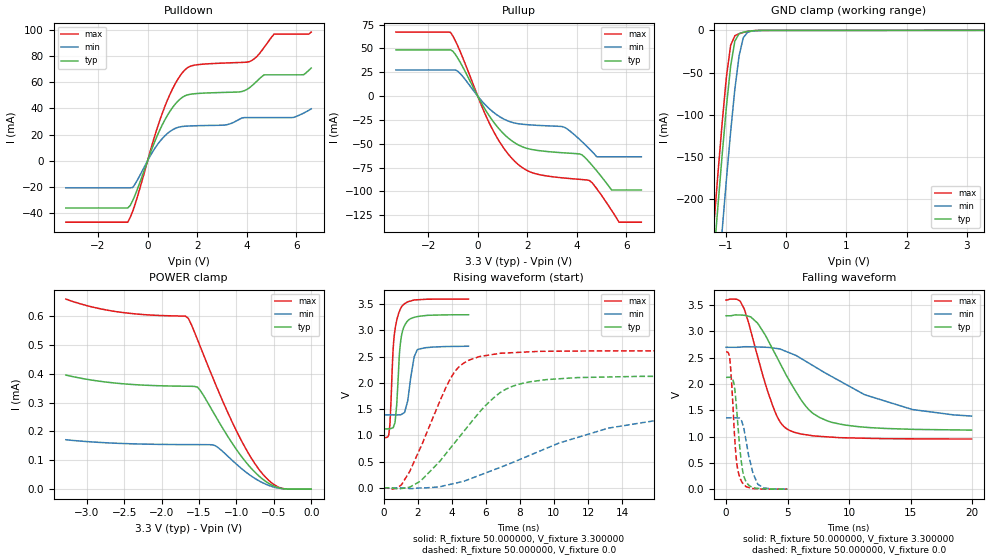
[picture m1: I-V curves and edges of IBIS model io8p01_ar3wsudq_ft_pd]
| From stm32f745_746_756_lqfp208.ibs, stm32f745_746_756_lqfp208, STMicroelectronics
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|   Model io8p01_ar3wsudq_ft_pd
[Model]  io8p01_ar3wsudq_ft_pd
Model_type I/O
Polarity   Non-Inverting
Enable   Active-Low
Vinl =   0.990000V
Vinh =   2.310000V
Vmeas =  1.650000V
Cref =   50.000000pF
Rref =   100.000000M
Vref =   0.0V
C_comp   3.843200pF   3.762100pF   3.937000pF
[Temperature Range]   25.000000   0.125000k   -40.000000
[Pullup Reference]   3.300000V   2.700000V   3.600000V
[Pulldown Reference]   0.0V   0.0V   0.0V
[POWER Clamp Reference]   3.300000V   2.700000V   3.600000V
[GND Clamp Reference]   0.0V   0.0V   0.0V
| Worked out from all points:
|   slope of the pulldown table from 0 to 0.495 V, typ, clamps not added: 20.9 ohm
|   slope of the pullup table from 0 to 0.495 V, typ, clamps not added: 22.6 ohm
|   GND clamp passes 1 mA (typ) near -0.62 V on its own axis
|   rising waveform, R_fixture 50.000000, V_fixture 3.300000: 20-80 % time 270ps typ, 352ps min, 283ps max; typ from 1.12 V to 3.3 V
|   rising waveform, R_fixture 50.000000, V_fixture 0.0: 20-80 % time 3.35ns typ, 6.78ns min, 2.11ns max; typ from 0 V to 2.13 V
|   falling waveform, R_fixture 50.000000, V_fixture 3.300000: 20-80 % time 3.21ns typ, 6.81ns min, 2.02ns max; typ from 3.3 V to 1.12 V
|   falling waveform, R_fixture 50.000000, V_fixture 0.0: 20-80 % time 504ps typ, 745ps min, 424ps max; typ from 2.13 V to 0 V
[Pulldown]
|Voltage   I(typ)   I(min)   I(max)
-3.3V     -36.18mA   -20.77mA   -47.07mA
-800mV    -36.18mA   -20.77mA   -47.07mA
-600mV    -30.5mA    -20.52mA   -38.69mA
700mV     31.4mA     19.11mA    41.71mA
1.2V      45.15mA    25.37mA    61.75mA
1.6V      50.35mA    26.5mA     71.06mA
3.1V      52.27mA    27.26mA    74.75mA
4.1V      55.7mA     33.01mA    75.8mA
4.7V      65.73mA    33.01mA    86.69mA
5.1V      65.73mA    33.01mA    96.89mA
6.3V      65.85mA    36.49mA    96.89mA
6.6V      70.9mA     39.7mA     98.44mA
[Pullup]
|Voltage   I(typ)   I(min)   I(max)
-3.3V     48.54mA    27.45mA    67.15mA
-1.1V     48.54mA    27.45mA    66.87mA
-700mV    35.13mA    23.48mA    46.33mA
500mV     -22.07mA   -14mA      -30.03mA
1.5V      -49.1mA    -28.3mA    -68.56mA
2.2V      -56.04mA   -30.32mA   -80.35mA
3.5V      -59.53mA   -32.72mA   -85.92mA
4.5V      -69.21mA   -55.27mA   -88.44mA
4.8V      -78.37mA   -63.6mA    -97.02mA
5.4V      -98.4mA    -63.6mA    -119.7mA
5.7V      -98.4mA    -63.6mA    -132.2mA
6.6V      -98.4mA    -63.6mA    -132.2mA
[GND_clamp]
|Voltage   I(typ)   I(min)   I(max)
-3.3V     -2.325A    -2.404A    -2.299A
-1.2V     -270.2mA   -361.4mA   -232.1mA
-1.13V    -207.3mA   -298.1mA   -169mA
-1.06V    -146.7mA   -236.2mA   -108.8mA
-990mV    -90.18mA   -176.4mA   -54.97mA
-920mV    -42.21mA   -120mA     -17.69mA
-850mV    -12.58mA   -69.47mA   -6.279mA
-780mV    -3.983mA   -30.01mA   -3.9mA
-710mV    -2.112mA   -8.623mA   -2.396mA
-640mV    -1.159mA   -2.292mA   -1.234mA
-570mV    -535.1uA   -830.5uA   -490.2uA
3.28V     81.28uA    57.87uA    93.98uA
[POWER_clamp]
|Voltage   I(typ)   I(min)   I(max)
-3.28V    395.3uA    171.3uA    658.7uA
-2.6V     367.1uA    159uA      614.9uA
-1.68V    356.7uA    154.4uA    599.4uA
-1.64V    356.5uA    154.4uA    590.8uA
-1.52V    353.6uA    154.3uA    518.3uA
-1.48V    341.1uA    154.2uA    492.3uA
-1.28V    253.6uA    150.4uA    364.2uA
-960mV    123.1uA    77.56uA    181.6uA
-720mV    50.52uA    32.03uA    76.18uA
-560mV    18.94uA    12.27uA    28.65uA
-440mV    5.104uA    3.69uA     7.327uA
0V        0A         0A         0A
[Ramp]
| variable   typ   min   max
dV/dt_r  1.27812/3.35922n   0.79776/6.76789n   1.56636/2.11275n
dV/dt_f  1.30194/3.21401n   0.74100/6.77912n   1.58738/2.02043n
R_load = 50.000000
[Rising Waveform]
R_fixture= 50.000000
V_fixture= 3.300000
V_fixture_min= 2.700000
V_fixture_max= 3.600000
|time   V(typ)   V(min)   V(max)
0s        1.123V     1.391V     953.9mV
360.4ps   1.126V     1.391V     1.185V
550.6ps   1.144V     1.391V     2.614V
660.7ps   1.236V     1.39V      3V
930.9ps   2.569V     1.392V     3.369V
1.031ns   2.863V     1.396V     3.438V
1.411ns   3.182V     1.655V     3.546V
1.782ns   3.248V     2.479V     3.579V
1.982ns   3.263V     2.635V     3.584V
4.985ns   3.299V     2.699V     3.598V
[Rising Waveform]
R_fixture= 50.000000
V_fixture= 0.0
V_fixture_min= 0.0
V_fixture_max= 0.0
|time   V(typ)   V(min)   V(max)
0s        357.3uV    204.3uV    681.7uV
1.041ns   -12.83mV   -1.324mV   56.47mV
2.162ns   126.4mV    -3.363mV   765.6mV
3.844ns   725.8mV    60.54mV    2.033V
4.364ns   935.4mV    98.84mV    2.285V
5.005ns   1.195V     160.8mV    2.432V
6.807ns   1.807V     384.6mV    2.563V
8.609ns   2.021V     623.3mV    2.593V
13.21ns   2.112V     1.138V     2.611V
19.94ns   2.128V     1.357V     2.611V
[Falling Waveform]
R_fixture= 50.000000
V_fixture= 3.300000
V_fixture_min= 2.700000
V_fixture_max= 3.600000
|time   V(typ)   V(min)   V(max)
0s        3.299V     2.699V     3.598V
920.9ps   3.313V     2.699V     3.608V
1.481ns   3.307V     2.709V     3.427V
2.563ns   3.158V     2.705V     2.526V
3.804ns   2.657V     2.686V     1.58V
5.045ns   2.105V     2.604V     1.132V
6.727ns   1.512V     2.397V     1.027V
8.609ns   1.27V      2.14V      989.3mV
15.14ns   1.139V     1.515V     957.7mV
19.94ns   1.123V     1.391V     953.9mV
[Falling Waveform]
R_fixture= 50.000000
V_fixture= 0.0
V_fixture_min= 0.0
V_fixture_max= 0.0
|time   V(typ)   V(min)   V(max)
0s        2.128V     1.357V     2.611V
300.3ps   2.129V     1.357V     2.489V
470.5ps   2.117V     1.357V     1.963V
620.6ps   2.029V     1.357V     1.315V
840.8ps   1.576V     1.359V     557.4mV
1.201ns   596.4mV    1.319V     176.8mV
1.622ns   146.7mV    928mV      49.83mV
2.182ns   33.62mV    307.5mV    12.06mV
2.583ns   15.14mV    93.93mV    6.521mV
4.985ns   357.3uV    204.3uV    681.7uV
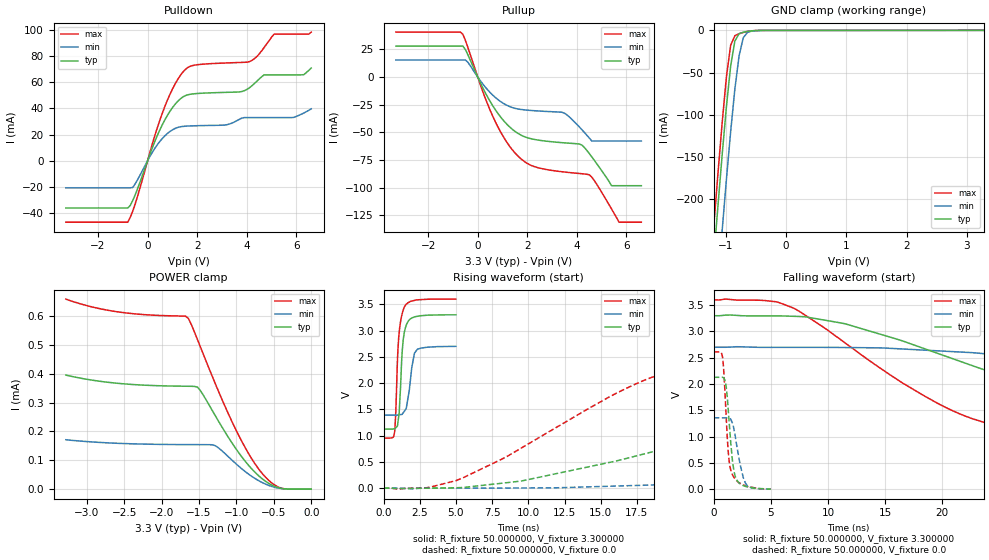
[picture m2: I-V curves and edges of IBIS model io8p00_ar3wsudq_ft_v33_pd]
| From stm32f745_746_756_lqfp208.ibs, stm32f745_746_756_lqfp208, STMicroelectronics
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|   Model io8p00_ar3wsudq_ft_v33_pd
[Model]  io8p00_ar3wsudq_ft_v33_pd
Model_type I/O
Polarity   Non-Inverting
Enable   Active-Low
Vinl =   0.990000V
Vinh =   2.310000V
Vmeas =  1.650000V
Cref =   50.000000pF
Rref =   100.000000M
Vref =   0.0V
C_comp   3.857500pF   3.762100pF   3.941700pF
[Temperature Range]   25.000000   0.125000k   -40.000000
[Pullup Reference]   3.300000V   2.700000V   3.600000V
[Pulldown Reference]   0.0V   0.0V   0.0V
[POWER Clamp Reference]   3.300000V   2.700000V   3.600000V
[GND Clamp Reference]   0.0V   0.0V   0.0V
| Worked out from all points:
|   slope of the pulldown table from 0 to 0.495 V, typ, clamps not added: 20.9 ohm
|   slope of the pullup table from 0 to 0.495 V, typ, clamps not added: 22.6 ohm
|   GND clamp passes 1 mA (typ) near -0.62 V on its own axis
|   rising waveform, R_fixture 50.000000, V_fixture 3.300000: 20-80 % time 276ps typ, 397ps min, 272ps max; typ from 1.12 V to 3.3 V
|   rising waveform, R_fixture 50.000000, V_fixture 0.0: 20-80 % time 19.7ns typ, 51.9ns min, 10.4ns max; typ from 0 V to 2.13 V
|   falling waveform, R_fixture 50.000000, V_fixture 3.300000: 20-80 % time 18.6ns typ, 38.4ns min, 11.3ns max; typ from 3.3 V to 1.12 V
|   falling waveform, R_fixture 50.000000, V_fixture 0.0: 20-80 % time 513ps typ, 708ps min, 436ps max; typ from 2.13 V to 0 V
[Pulldown]
|Voltage   I(typ)   I(min)   I(max)
-3.3V     -36.18mA   -20.77mA   -47.07mA
-800mV    -36.18mA   -20.77mA   -47.07mA
-600mV    -30.5mA    -20.52mA   -38.69mA
700mV     31.4mA     19.11mA    41.71mA
1.2V      45.15mA    25.37mA    61.75mA
1.6V      50.35mA    26.5mA     71.06mA
3.1V      52.27mA    27.26mA    74.75mA
4.1V      55.7mA     32.99mA    75.8mA
4.7V      65.71mA    32.99mA    86.63mA
5.1V      65.71mA    32.99mA    96.88mA
6.3V      65.85mA    36.49mA    96.88mA
6.6V      70.9mA     39.7mA     98.44mA
[Pullup]
|Voltage   I(typ)   I(min)   I(max)
-3.3V     28.03mA    15.43mA    40.67mA
-700mV    28.03mA    15.43mA    40.67mA
-400mV    20.31mA    13.47mA    26.93mA
600mV     -25.77mA   -16.23mA   -35.13mA
1.6V      -50.64mA   -28.81mA   -70.96mA
2.3V      -56.49mA   -30.48mA   -81.16mA
3.5V      -59.53mA   -32.72mA   -85.92mA
4.2V      -61.52mA   -47.6mA    -87.46mA
4.5V      -69.21mA   -55.14mA   -88.44mA
5.4V      -98.3mA    -57.9mA    -119.4mA
5.7V      -98.3mA    -57.9mA    -131.3mA
6.6V      -98.3mA    -57.9mA    -131.3mA
[GND_clamp]
|Voltage   I(typ)   I(min)   I(max)
-3.3V     -2.333A    -2.407A    -2.313A
-1.2V     -270.2mA   -361.4mA   -232.1mA
-1.13V    -207.3mA   -298.1mA   -169mA
-1.06V    -146.7mA   -236.2mA   -108.8mA
-990mV    -90.18mA   -176.4mA   -54.97mA
-920mV    -42.21mA   -120mA     -17.69mA
-850mV    -12.58mA   -69.47mA   -6.279mA
-780mV    -3.983mA   -30.01mA   -3.9mA
-710mV    -2.112mA   -8.623mA   -2.396mA
-640mV    -1.159mA   -2.292mA   -1.234mA
-570mV    -535.1uA   -830.5uA   -490.2uA
3.28V     81.28uA    57.87uA    93.98uA
[POWER_clamp]
|Voltage   I(typ)   I(min)   I(max)
-3.28V    395.3uA    171.3uA    658.7uA
-2.6V     367.1uA    159uA      614.9uA
-1.68V    356.7uA    154.4uA    599.4uA
-1.64V    356.5uA    154.4uA    590.8uA
-1.52V    353.6uA    154.3uA    518.3uA
-1.48V    341.1uA    154.2uA    492.3uA
-1.28V    253.6uA    150.4uA    364.2uA
-960mV    123.1uA    77.55uA    181.6uA
-720mV    50.52uA    32.03uA    76.18uA
-560mV    18.94uA    12.27uA    28.65uA
-440mV    5.104uA    3.69uA     7.327uA
0V        0A         0A         0A
[Ramp]
| variable   typ   min   max
dV/dt_r  1.27668/19.66164n   0.81522/51.92057n   1.56654/10.38570n
dV/dt_f  1.30572/18.58654n   0.78528/38.57212n   1.58743/11.31090n
R_load = 50.000000
[Rising Waveform]
R_fixture= 50.000000
V_fixture= 3.300000
V_fixture_min= 2.700000
V_fixture_max= 3.600000
|time   V(typ)   V(min)   V(max)
0s        1.123V     1.39V      953.1mV
760.8ps   1.131V     1.39V      1.076V
840.8ps   1.15V      1.39V      1.456V
1.041ns   1.364V     1.394V     2.869V
1.281ns   2.597V     1.408V     3.32V
1.441ns   2.982V     1.469V     3.454V
1.562ns   3.1V       1.52V      3.5V
2.132ns   3.258V     2.57V      3.573V
2.332ns   3.271V     2.644V     3.584V
4.985ns   3.299V     2.699V     3.599V
[Rising Waveform]
R_fixture= 50.000000
V_fixture= 0.0
V_fixture_min= 0.0
V_fixture_max= 0.0
|time   V(typ)   V(min)   V(max)
0s        122.9nV    336.7nV    642.2nV
3.003ns   -461.2uV   -682.5uV   8.405mV
5.506ns   12.51mV    -96.65uV   200.1mV
19.02ns   722.6mV    63.66mV    2.156V
30.53ns   1.491V     229.7mV    2.528V
40.04ns   1.895V     386mV      2.58V
55.06ns   2.057V     671.2mV    2.604V
87.09ns   2.115V     1.113V     2.611V
117.6ns   2.128V     1.3V       2.611V
249.2ns   2.128V     1.358V     2.611V
[Falling Waveform]
R_fixture= 50.000000
V_fixture= 3.300000
V_fixture_min= 2.700000
V_fixture_max= 3.600000
|time   V(typ)   V(min)   V(max)
0s        3.299V     2.699V     3.599V
7.007ns   3.288V     2.697V     3.441V
16.52ns   2.819V     2.666V     2.019V
22.52ns   2.357V     2.597V     1.348V
32.53ns   1.666V     2.393V     1.062V
38.54ns   1.41V      2.26V      1.026V
47.55ns   1.262V     2.05V      993.2mV
62.56ns   1.183V     1.725V     967.2mV
89.59ns   1.144V     1.511V     954.9mV
249.2ns   1.123V     1.39V      953.1mV
[Falling Waveform]
R_fixture= 50.000000
V_fixture= 0.0
V_fixture_min= 0.0
V_fixture_max= 0.0
|time   V(typ)   V(min)   V(max)
0s        2.128V     1.358V     2.611V
780.8ps   2.126V     1.357V     2.489V
860.9ps   2.118V     1.357V     2.293V
1.091ns   1.941V     1.357V     1.358V
1.261ns   1.522V     1.352V     721.8mV
1.411ns   1.091V     1.341V     437.8mV
1.622ns   573.9mV    1.262V     282mV
1.962ns   198.5mV    893mV      169.3mV
2.763ns   53.2mV     118.9mV    62.26mV
4.985ns   122.9nV    336.7nV    642.2nV
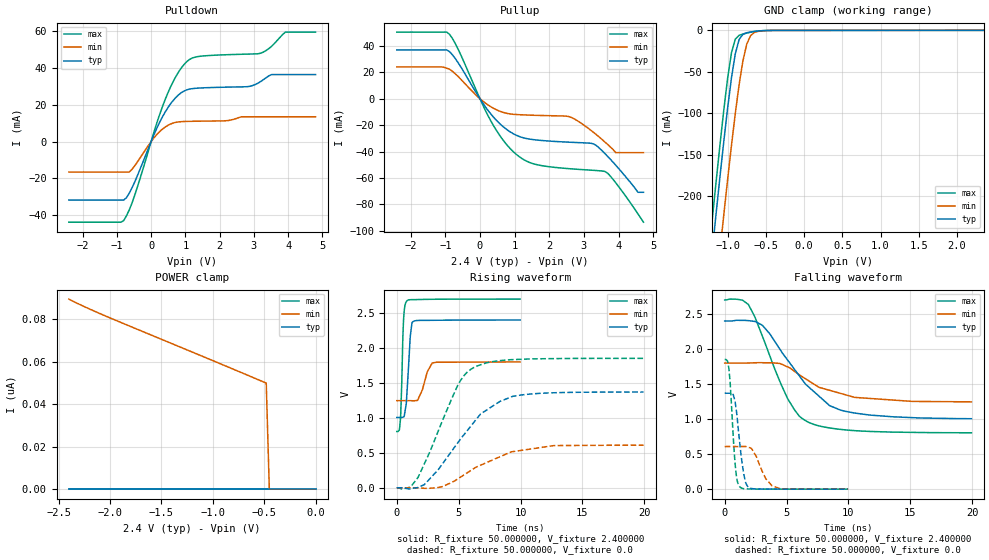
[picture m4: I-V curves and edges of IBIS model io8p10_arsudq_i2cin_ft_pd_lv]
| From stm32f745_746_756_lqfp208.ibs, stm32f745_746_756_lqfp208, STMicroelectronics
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|   Model io8p10_arsudq_i2cin_ft_pd_lv
[Model]  io8p10_arsudq_i2cin_ft_pd_lv
Model_type I/O
Polarity   Non-Inverting
Enable   Active-Low
Vinl =   0.720000V
Vinh =   1.680000V
Vmeas =  1.200000V
Cref =   40.000000pF
Rref =   100.000000M
Vref =   0.0V
C_comp   2.230300pF   2.174000pF   2.332300pF
[Temperature Range]   25.000000   0.125000k   -40.000000
[Pullup Reference]   2.400000V   1.800000V   2.700000V
[Pulldown Reference]   0.0V   0.0V   0.0V
[POWER Clamp Reference]   2.400000V   1.800000V   2.700000V
[GND Clamp Reference]   0.0V   0.0V   0.0V
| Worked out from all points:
|   slope of the pulldown table from 0 to 0.36 V, typ, clamps not added: 25 ohm
|   slope of the pullup table from 0 to 0.36 V, typ, clamps not added: 27.7 ohm
|   GND clamp passes 1 mA (typ) near -0.62 V on its own axis
|   rising waveform, R_fixture 50.000000, V_fixture 2.400000: 20-80 % time 278ps typ, 607ps min, 184ps max; typ from 1 V to 2.4 V
|   rising waveform, R_fixture 50.000000, V_fixture 0.0: 20-80 % time 3.71ns typ, 4.01ns min, 2.67ns max; typ from 0 V to 1.37 V
|   falling waveform, R_fixture 50.000000, V_fixture 2.400000: 20-80 % time 3.89ns typ, 3.98ns min, 2.72ns max; typ from 2.4 V to 1 V
|   falling waveform, R_fixture 50.000000, V_fixture 0.0: 20-80 % time 529ps typ, 975ps min, 384ps max; typ from 1.37 V to 0 V
[Pulldown]
|Voltage   I(typ)   I(min)   I(max)
-2.4V     -31.73mA   -16.51mA   -43.74mA
-800mV    -31.73mA   -16.51mA   -42.87mA
-480mV    -21.98mA   -13.17mA   -29.2mA
80mV      3.63mA     1.966mA    5.014mA
480mV     18.15mA    8.738mA    26.02mA
800mV     25.38mA    10.72mA    37.77mA
1.12V     28.53mA    11.02mA    44.6mA
2.8V      29.84mA    13.49mA    47.53mA
3.2V      32.65mA    13.49mA    48.04mA
3.52V     36.42mA    13.49mA    51.83mA
3.92V     36.42mA    13.49mA    59.49mA
4.8V      36.42mA    13.49mA    59.49mA
[Pullup]
|Voltage   I(typ)   I(min)   I(max)
-2.4V     36.91mA    24.03mA    50.37mA
-960mV    36.91mA    23.05mA    50.37mA
-640mV    27.65mA    17.03mA    37.99mA
320mV     -11.75mA   -6.207mA   -17.08mA
960mV     -26.47mA   -11.82mA   -40.02mA
1.52V     -30.88mA   -12.51mA   -49.05mA
2.56V     -32.88mA   -13.48mA   -52.9mA
3.28V     -34.19mA   -25.52mA   -54.18mA
3.6V      -41.31mA   -32.62mA   -54.97mA
3.92V     -50.32mA   -40.8mA    -63.63mA
4.56V     -70.8mA    -40.8mA    -87.08mA
4.72V     -70.8mA    -40.8mA    -93.4mA
[GND_clamp]
|Voltage   I(typ)   I(min)   I(max)
-2.4V     -1.424A    -1.508A    -1.393A
-1.25V    -311.2mA   -401.9mA   -273.3mA
-1.2V     -265.4mA   -356.1mA   -227.2mA
-1.15V    -220.4mA   -310.8mA   -181.9mA
-1.1V     -176.3mA   -266.2mA   -137.9mA
-1.05V    -133.8mA   -222.5mA   -95.87mA
-950mV    -57.3mA    -138.9mA   -26.99mA
-900mV    -28.28mA   -100.4mA   -10.6mA
-850mV    -11.02mA   -65.54mA   -5.972mA
-750mV    -2.846mA   -16.51mA   -3.192mA
-600mV    -761.3uA   -1.173mA   -751.9uA
2.35V     58.09uA    37.92uA    67.25uA
[POWER_clamp]
|Voltage   I(typ)   I(min)   I(max)
-2.4V     0A         89.62nA    0A
-2.04V    0A         81.57nA    0A
-480mV    0A         50.01nA    0A
-450mV    0A         0A         0A
0V        0A         0A         0A
[Ramp]
| variable   typ   min   max
dV/dt_r  0.82140/3.70323n   0.36557/4.01414n   1.11078/2.67231n
dV/dt_f  0.83346/3.89446n   0.33294/4.04052n   1.13600/2.72263n
R_load = 50.000000
[Rising Waveform]
R_fixture= 50.000000
V_fixture= 2.400000
V_fixture_min= 1.800000
V_fixture_max= 2.700000
|time   V(typ)   V(min)   V(max)
0s        1.005V     1.245V     804.2mV
200.2ps   1.005V     1.245V     825.1mV
300.3ps   1.005V     1.245V     988.7mV
560.6ps   1.014V     1.246V     2.44V
820.8ps   1.353V     1.246V     2.673V
1.101ns   2.18V      1.245V     2.689V
1.341ns   2.38V      1.244V     2.69V
1.682ns   2.392V     1.252V     2.691V
2.883ns   2.395V     1.786V     2.695V
9.97ns    2.399V     1.799V     2.698V
[Rising Waveform]
R_fixture= 50.000000
V_fixture= 0.0
V_fixture_min= 0.0
V_fixture_max= 0.0
|time   V(typ)   V(min)   V(max)
0s        169.1uV    66.56uV    559.6uV
1.121ns   -14.43mV   129.7uV    14.51mV
1.722ns   5.603mV    -1.064mV   149.4mV
3.323ns   253.4mV    4.117mV    799mV
4.925ns   642.3mV    126.4mV    1.464V
6.246ns   939mV      277mV      1.721V
6.807ns   1.059V     325.4mV    1.761V
9.369ns   1.308V     516.9mV    1.833V
12.73ns   1.359V     603.3mV    1.847V
19.94ns   1.369V     608.4mV    1.851V
[Falling Waveform]
R_fixture= 50.000000
V_fixture= 2.400000
V_fixture_min= 1.800000
V_fixture_max= 2.700000
|time   V(typ)   V(min)   V(max)
0s        2.399V     1.799V     2.698V
1.441ns   2.408V     1.799V     2.695V
1.922ns   2.404V     1.8V       2.631V
3.043ns   2.338V     1.804V     2.183V
5.085ns   1.841V     1.744V     1.292V
6.006ns   1.623V     1.636V     1.047V
6.727ns   1.468V     1.553V     958.2mV
8.488ns   1.191V     1.41V      873.1mV
9.77ns    1.11V      1.346V     845.1mV
19.94ns   1.005V     1.245V     804.2mV
[Falling Waveform]
R_fixture= 50.000000
V_fixture= 0.0
V_fixture_min= 0.0
V_fixture_max= 0.0
|time   V(typ)   V(min)   V(max)
0s        1.369V     608.4mV    1.851V
340.3ps   1.369V     608.4mV    1.717V
440.4ps   1.369V     608.4mV    1.52V
700.7ps   1.342V     608.3mV    718.3mV
940.9ps   1.121V     608mV      197.1mV
1.221ns   650.7mV    607.9mV    34.2mV
1.542ns   212.1mV    608.9mV    6.783mV
2.022ns   17.91mV    591.1mV    2.687mV
3.844ns   1.284mV    46.71mV    1.333mV
9.97ns    169.1uV    66.56uV    559.6uV
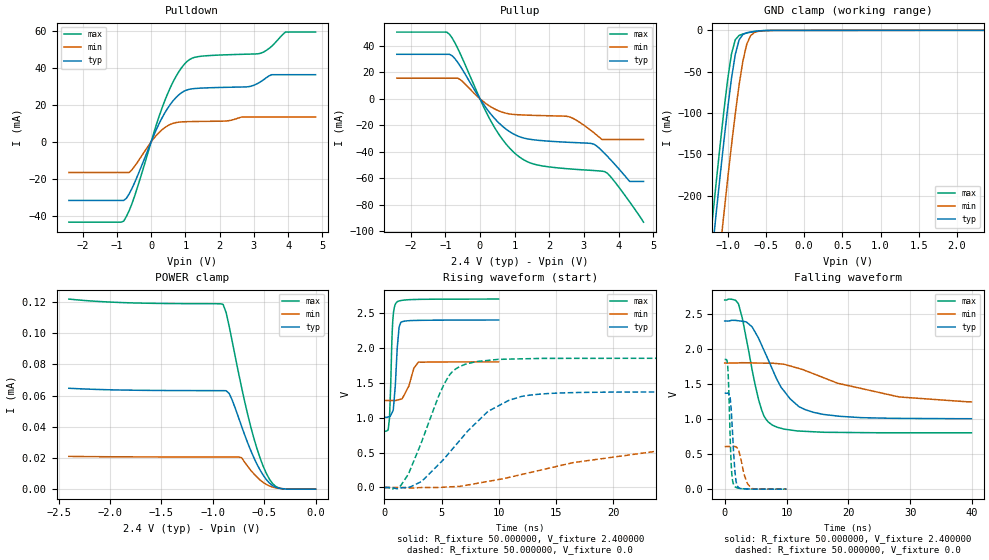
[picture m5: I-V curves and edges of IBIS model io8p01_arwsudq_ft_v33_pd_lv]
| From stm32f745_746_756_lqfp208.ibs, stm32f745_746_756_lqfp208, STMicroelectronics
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|   Model io8p01_arwsudq_ft_v33_pd_lv
[Model]  io8p01_arwsudq_ft_v33_pd_lv
Model_type I/O
Polarity   Non-Inverting
Enable   Active-Low
Vinl =   0.720000V
Vinh =   1.680000V
Vmeas =  1.200000V
Cref =   50.000000pF
Rref =   100.000000M
Vref =   0.0V
C_comp   2.828400pF   2.771400pF   2.910300pF
[Temperature Range]   25.000000   0.125000k   -40.000000
[Pullup Reference]   2.400000V   1.800000V   2.700000V
[Pulldown Reference]   0.0V   0.0V   0.0V
[POWER Clamp Reference]   2.400000V   1.800000V   2.700000V
[GND Clamp Reference]   0.0V   0.0V   0.0V
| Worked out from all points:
|   slope of the pulldown table from 0 to 0.36 V, typ, clamps not added: 25 ohm
|   slope of the pullup table from 0 to 0.36 V, typ, clamps not added: 27.7 ohm
|   GND clamp passes 1 mA (typ) near -0.62 V on its own axis
|   rising waveform, R_fixture 50.000000, V_fixture 2.400000: 20-80 % time 323ps typ, 711ps min, 222ps max; typ from 1 V to 2.4 V
|   rising waveform, R_fixture 50.000000, V_fixture 0.0: 20-80 % time 4.72ns typ, 12.1ns min, 2.67ns max; typ from 0 V to 1.37 V
|   falling waveform, R_fixture 50.000000, V_fixture 2.400000: 20-80 % time 5ns typ, 13ns min, 2.68ns max; typ from 2.4 V to 1 V
|   falling waveform, R_fixture 50.000000, V_fixture 0.0: 20-80 % time 552ps typ, 1.05ns min, 407ps max; typ from 1.37 V to 0 V
[Pulldown]
|Voltage   I(typ)   I(min)   I(max)
-2.4V     -31.66mA   -16.51mA   -43.43mA
-800mV    -31.66mA   -16.51mA   -42.86mA
-480mV    -21.98mA   -13.17mA   -29.2mA
80mV      3.63mA     1.966mA    5.014mA
480mV     18.15mA    8.738mA    26.02mA
800mV     25.38mA    10.72mA    37.77mA
1.12V     28.53mA    11.02mA    44.6mA
2.8V      29.84mA    13.48mA    47.53mA
3.2V      32.65mA    13.48mA    48.04mA
3.52V     36.42mA    13.48mA    51.83mA
3.92V     36.42mA    13.48mA    59.48mA
4.8V      36.42mA    13.48mA    59.48mA
[Pullup]
|Voltage   I(typ)   I(min)   I(max)
-2.4V     33.56mA    15.57mA    50.34mA
-960mV    33.56mA    15.57mA    50.34mA
-800mV    32.44mA    15.57mA    45.78mA
-560mV    24.28mA    14.31mA    33.53mA
320mV     -11.75mA   -6.207mA   -17.08mA
960mV     -26.47mA   -11.82mA   -40.02mA
1.52V     -30.88mA   -12.51mA   -49.05mA
2.56V     -32.88mA   -13.49mA   -52.9mA
3.28V     -34.2mA    -25.51mA   -54.18mA
3.6V      -41.34mA   -30.76mA   -55mA
4.32V     -62.43mA   -30.76mA   -77.88mA
4.72V     -62.43mA   -30.76mA   -93.2mA
[GND_clamp]
|Voltage   I(typ)   I(min)   I(max)
-2.4V     -1.428A    -1.51A     -1.4A
-1.2V     -266.4mA   -356.3mA   -229.4mA
-1.15V    -221.3mA   -311mA     -184.1mA
-1.1V     -177.3mA   -266.4mA   -140mA
-1.05V    -134.8mA   -222.7mA   -97.98mA
-950mV    -58.22mA   -139.2mA   -28.55mA
-900mV    -29.04mA   -100.6mA   -11.28mA
-850mV    -11.42mA   -65.77mA   -6.081mA
-750mV    -2.864mA   -16.63mA   -3.193mA
-700mV    -1.925mA   -6.327mA   -2.195mA
-600mV    -761.3uA   -1.176mA   -751.9uA
2.35V     58.09uA    37.92uA    67.25uA
[POWER_clamp]
|Voltage   I(typ)   I(min)   I(max)
-2.4V     64.71uA    21.03uA    121.9uA
-1.86V    63.55uA    20.74uA    119.6uA
-900mV    63.18uA    20.63uA    118.5uA
-870mV    63.14uA    20.63uA    113.2uA
-840mV    61.36uA    20.62uA    104.3uA
-720mV    40.37uA    20.18uA    65.28uA
-630mV    24.69uA    12.08uA    39.85uA
-540mV    12.26uA    5.907uA    20uA
-480mV    6.236uA    3.061uA    10.23uA
-420mV    2.4uA      1.365uA    3.726uA
-360mV    667.9nA    564nA      839.6nA
0V        0A         0A         0A
[Ramp]
| variable   typ   min   max
dV/dt_r  0.82164/4.71231n   0.38152/12.87060n   1.11030/2.66844n
dV/dt_f  0.83700/5.00385n   0.32262/13.04754n   1.13709/2.68087n
R_load = 50.000000
[Rising Waveform]
R_fixture= 50.000000
V_fixture= 2.400000
V_fixture_min= 1.800000
V_fixture_max= 2.700000
|time   V(typ)   V(min)   V(max)
0s        1.005V     1.245V     804.5mV
320.3ps   1.01V      1.245V     823.2mV
440.4ps   1.015V     1.245V     991.1mV
720.7ps   1.09V      1.245V     2.368V
940.9ps   1.443V     1.245V     2.62V
1.041ns   1.754V     1.248V     2.648V
1.281ns   2.298V     1.258V     2.671V
1.461ns   2.368V     1.266V     2.678V
2.963ns   2.394V     1.796V     2.694V
9.97ns    2.399V     1.799V     2.699V
[Rising Waveform]
R_fixture= 50.000000
V_fixture= 0.0
V_fixture_min= 0.0
V_fixture_max= 0.0
|time   V(typ)   V(min)   V(max)
0s        86.79uV    35.83uV    200.4uV
1.361ns   -9.078mV   -362.6uV   17.04mV
2.082ns   3.157mV    -5.824mV   188.2mV
5.205ns   409.6mV    4.315mV    1.478V
6.006ns   563.9mV    11.06mV    1.669V
7.127ns   779.9mV    31.27mV    1.768V
9.049ns   1.09V      87.08mV    1.82V
12.73ns   1.324V     214.5mV    1.845V
25.23ns   1.369V     551.5mV    1.85V
39.88ns   1.369V     608.5mV    1.85V
[Falling Waveform]
R_fixture= 50.000000
V_fixture= 2.400000
V_fixture_min= 1.800000
V_fixture_max= 2.700000
|time   V(typ)   V(min)   V(max)
0s        2.399V     1.799V     2.699V
2.242ns   2.402V     1.801V     2.639V
4.404ns   2.318V     1.802V     1.718V
5.526ns   2.143V     1.799V     1.262V
6.406ns   1.97V      1.798V     1.036V
7.768ns   1.698V     1.797V     912mV
10.57ns   1.289V     1.758V     844.7mV
14.49ns   1.093V     1.641V     818.4mV
28.19ns   1.01V      1.316V     804.7mV
39.88ns   1.005V     1.245V     804.5mV
[Falling Waveform]
R_fixture= 50.000000
V_fixture= 0.0
V_fixture_min= 0.0
V_fixture_max= 0.0
|time   V(typ)   V(min)   V(max)
0s        1.369V     608.5mV    1.85V
460.5ps   1.37V      608.3mV    1.79V
660.7ps   1.366V     608.2mV    1.412V
1.041ns   1.152V     608mV      367.1mV
1.481ns   468.4mV    609.1mV    57.68mV
1.822ns   119.8mV    605.7mV    25.95mV
2.282ns   19.63mV    550mV      13.19mV
3.143ns   4.144mV    207.1mV    5.114mV
4.364ns   1.776mV    9.239mV    1.656mV
9.97ns    86.79uV    35.83uV    200.4uV
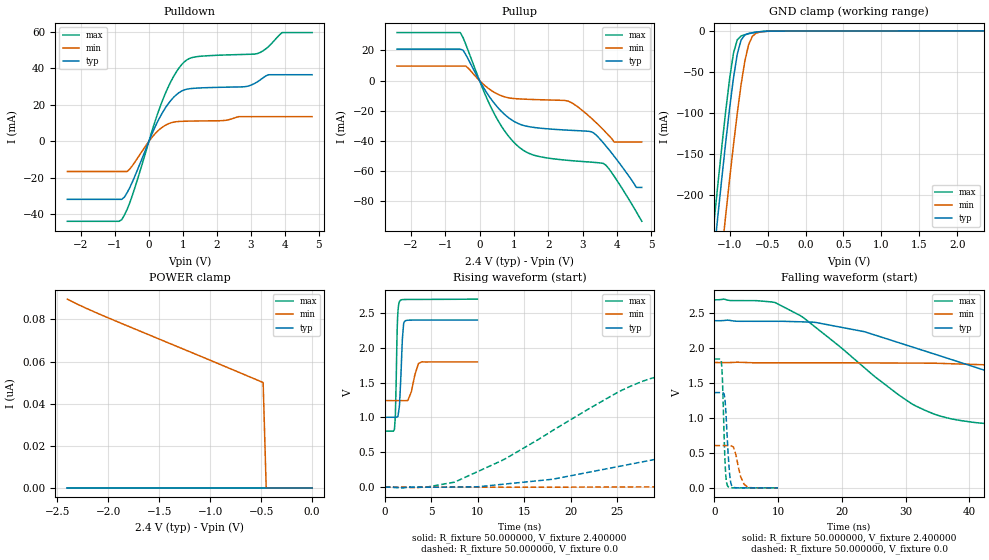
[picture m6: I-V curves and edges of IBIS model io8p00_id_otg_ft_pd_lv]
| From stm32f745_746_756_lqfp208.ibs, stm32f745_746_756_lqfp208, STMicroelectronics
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|   Model io8p00_id_otg_ft_pd_lv
[Model]  io8p00_id_otg_ft_pd_lv
Model_type I/O
Polarity   Non-Inverting
Enable   Active-Low
Vinl =   0.720000V
Vinh =   1.680000V
Vmeas =  1.200000V
Cref =   50.000000pF
Rref =   100.000000M
Vref =   0.0V
C_comp   2.229800pF   2.169700pF   2.325100pF
[Temperature Range]   25.000000   0.125000k   -40.000000
[Pullup Reference]   2.400000V   1.800000V   2.700000V
[Pulldown Reference]   0.0V   0.0V   0.0V
[POWER Clamp Reference]   2.400000V   1.800000V   2.700000V
[GND Clamp Reference]   0.0V   0.0V   0.0V
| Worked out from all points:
|   slope of the pulldown table from 0 to 0.36 V, typ, clamps not added: 25 ohm
|   slope of the pullup table from 0 to 0.36 V, typ, clamps not added: 27.7 ohm
|   GND clamp passes 1 mA (typ) near -0.62 V on its own axis
|   rising waveform, R_fixture 50.000000, V_fixture 2.400000: 20-80 % time 270ps typ, 604ps min, 182ps max; typ from 1 V to 2.4 V
|   rising waveform, R_fixture 50.000000, V_fixture 0.0: 20-80 % time 32.9ns typ, 82.2ns min, 14.6ns max; typ from 0 V to 1.37 V
|   falling waveform, R_fixture 50.000000, V_fixture 2.400000: 20-80 % time 29.6ns typ, 74.5ns min, 15.8ns max; typ from 2.4 V to 1 V
|   falling waveform, R_fixture 50.000000, V_fixture 0.0: 20-80 % time 522ps typ, 974ps min, 382ps max; typ from 1.37 V to 0 V
[Pulldown]
|Voltage   I(typ)   I(min)   I(max)
-2.4V     -31.73mA   -16.51mA   -43.74mA
-800mV    -31.73mA   -16.51mA   -42.87mA
-480mV    -21.97mA   -13.17mA   -29.2mA
80mV      3.629mA    1.966mA    5.013mA
480mV     18.15mA    8.736mA    26.01mA
800mV     25.37mA    10.71mA    37.77mA
1.12V     28.53mA    11.02mA    44.6mA
2.8V      29.83mA    13.48mA    47.51mA
3.2V      32.64mA    13.48mA    48.03mA
3.52V     36.41mA    13.48mA    51.82mA
3.92V     36.41mA    13.48mA    59.47mA
4.8V      36.41mA    13.48mA    59.47mA
[Pullup]
|Voltage   I(typ)   I(min)   I(max)
-2.4V     20.88mA    9.659mA    31.9mA
-560mV    20.88mA    9.659mA    31.9mA
-400mV    17.28mA    9.659mA    24.06mA
320mV     -11.75mA   -6.206mA   -17.08mA
960mV     -26.47mA   -11.82mA   -40.02mA
1.52V     -30.88mA   -12.51mA   -49.05mA
2.56V     -32.88mA   -13.48mA   -52.9mA
3.28V     -34.19mA   -25.52mA   -54.18mA
3.6V      -41.31mA   -32.62mA   -54.98mA
3.92V     -50.32mA   -40.8mA    -63.62mA
4.56V     -70.9mA    -40.8mA    -87.08mA
4.72V     -70.9mA    -40.8mA    -93.4mA
[GND_clamp]
|Voltage   I(typ)   I(min)   I(max)
-2.4V     -1.424A    -1.508A    -1.393A
-1.25V    -311.2mA   -401.9mA   -273.3mA
-1.2V     -265.4mA   -356.1mA   -227.2mA
-1.15V    -220.4mA   -310.8mA   -181.9mA
-1.1V     -176.3mA   -266.2mA   -137.9mA
-1.05V    -133.8mA   -222.5mA   -95.89mA
-950mV    -57.33mA   -138.9mA   -27.03mA
-900mV    -28.31mA   -100.4mA   -10.67mA
-850mV    -11.07mA   -65.56mA   -6.047mA
-750mV    -2.904mA   -16.55mA   -3.26mA
-600mV    -808.2uA   -1.212mA   -806.8uA
2.35V     242.6uA    152uA      283.9uA
[POWER_clamp]
|Voltage   I(typ)   I(min)   I(max)
-2.4V     0A         89.62nA    0A
-2.04V    0A         81.58nA    0A
-480mV    0A         50.01nA    0A
-450mV    0A         0A         0A
0V        0A         0A         0A
[Ramp]
| variable   typ   min   max
dV/dt_r  0.81942/32.88593n   0.36131/85.13700n   1.10850/14.58604n
dV/dt_f  0.83658/29.57145n   0.32832/79.61571n   1.13579/15.78053n
R_load = 50.000000
[Rising Waveform]
R_fixture= 50.000000
V_fixture= 2.400000
V_fixture_min= 1.800000
V_fixture_max= 2.700000
|time   V(typ)   V(min)   V(max)
0s        1.002V     1.241V     802.8mV
1.041ns   1.003V     1.242V     829.6mV
1.141ns   1.002V     1.242V     1.04V
1.381ns   1.011V     1.242V     2.438V
1.642ns   1.333V     1.242V     2.673V
1.902ns   2.137V     1.242V     2.689V
2.162ns   2.382V     1.24V      2.69V
2.843ns   2.395V     1.362V     2.691V
3.644ns   2.396V     1.773V     2.692V
9.97ns    2.396V     1.796V     2.696V
[Rising Waveform]
R_fixture= 50.000000
V_fixture= 0.0
V_fixture_min= 0.0
V_fixture_max= 0.0
|time   V(typ)   V(min)   V(max)
0s        4.159nV    252.6nV    1.587nV
7.508ns   2.136mV    -50.35uV   72.52mV
18.02ns   113.2mV    450.3uV    807.5mV
27.03ns   345.1mV    4.157mV    1.48V
32.03ns   478mV      10.29mV    1.661V
37.54ns   640.1mV    25.87mV    1.745V
58.06ns   1.111V     86.07mV    1.826V
76.58ns   1.302V     176.4mV    1.843V
148.1ns   1.364V     487.9mV    1.847V
249.2ns   1.366V     606.6mV    1.847V
[Falling Waveform]
R_fixture= 50.000000
V_fixture= 2.400000
V_fixture_min= 1.800000
V_fixture_max= 2.700000
|time   V(typ)   V(min)   V(max)
0s        2.396V     1.796V     2.696V
9.51ns    2.388V     1.792V     2.657V
16.02ns   2.369V     1.792V     2.291V
31.03ns   2.02V      1.788V     1.202V
36.54ns   1.859V     1.781V     1.003V
45.55ns   1.593V     1.755V     897.2mV
59.56ns   1.242V     1.706V     846.6mV
85.59ns   1.074V     1.56V      816.2mV
124.1ns   1.024V     1.378V     804.8mV
249.2ns   1.002V     1.241V     802.8mV
[Falling Waveform]
R_fixture= 50.000000
V_fixture= 0.0
V_fixture_min= 0.0
V_fixture_max= 0.0
|time   V(typ)   V(min)   V(max)
0s        1.366V     606.6mV    1.847V
1.061ns   1.365V     606.5mV    1.815V
1.241ns   1.366V     606.5mV    1.566V
1.682ns   1.229V     606.3mV    320.7mV
1.842ns   999.4mV    606mV      110.4mV
2.042ns   652mV      605.8mV    31.67mV
2.482ns   115.9mV    608.2mV    2.943mV
2.843ns   16.55mV    591.6mV    655.5uV
4.645ns   56.61uV    52.07mV    22.82uV
9.97ns    4.159nV    252.6nV    1.587nV
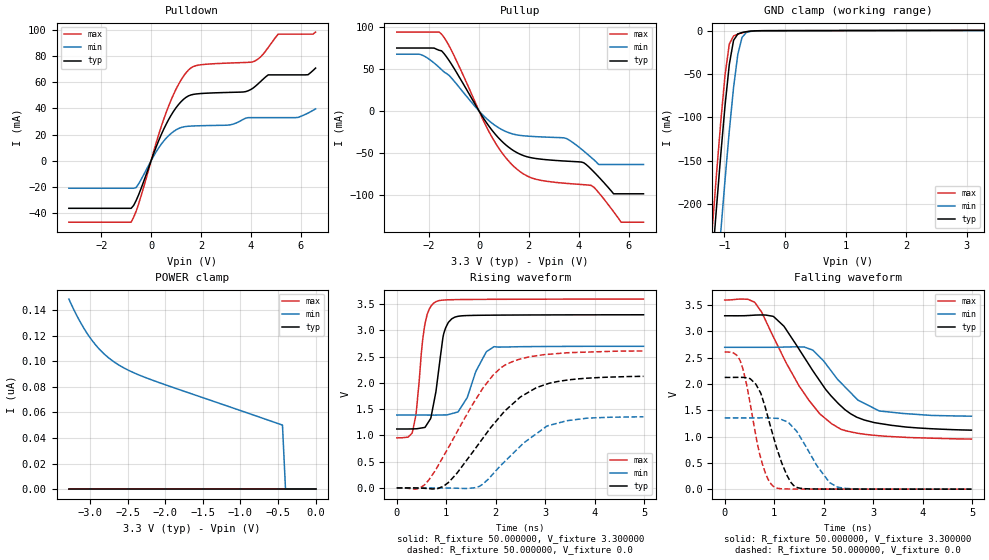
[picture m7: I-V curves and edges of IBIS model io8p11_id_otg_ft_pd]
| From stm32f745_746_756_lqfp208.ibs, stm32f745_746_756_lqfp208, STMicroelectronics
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|   Model io8p11_id_otg_ft_pd
[Model]  io8p11_id_otg_ft_pd
Model_type I/O
Polarity   Non-Inverting
Enable   Active-Low
Vinl =   0.990000V
Vinh =   2.310000V
Vmeas =  1.650000V
Cref =   30.000000pF
Rref =   100.000000M
Vref =   0.0V
C_comp   2.283100pF   2.214400pF   2.357400pF
[Temperature Range]   25.000000   0.125000k   -40.000000
[Pullup Reference]   3.300000V   2.700000V   3.600000V
[Pulldown Reference]   0.0V   0.0V   0.0V
[POWER Clamp Reference]   3.300000V   2.700000V   3.600000V
[GND Clamp Reference]   0.0V   0.0V   0.0V
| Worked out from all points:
|   slope of the pulldown table from 0 to 0.495 V, typ, clamps not added: 20.9 ohm
|   slope of the pullup table from 0 to 0.495 V, typ, clamps not added: 22.6 ohm
|   GND clamp passes 1 mA (typ) near -0.62 V on its own axis
|   rising waveform, R_fixture 50.000000, V_fixture 3.300000: 20-80 % time 198ps typ, 345ps min, 162ps max; typ from 1.12 V to 3.29 V
|   rising waveform, R_fixture 50.000000, V_fixture 0.0: 20-80 % time 1.13ns typ, 948ps min, 1ns max; typ from 0 V to 2.12 V
|   falling waveform, R_fixture 50.000000, V_fixture 3.300000: 20-80 % time 1.01ns typ, 783ps min, 983ps max; typ from 3.29 V to 1.12 V
|   falling waveform, R_fixture 50.000000, V_fixture 0.0: 20-80 % time 414ps typ, 536ps min, 330ps max; typ from 2.12 V to 0 V
[Pulldown]
|Voltage   I(typ)   I(min)   I(max)
-3.3V     -36.46mA   -21.1mA    -47.09mA
-800mV    -36.46mA   -21.1mA    -47.09mA
-600mV    -30.5mA    -20.54mA   -38.68mA
700mV     31.39mA    19.11mA    41.7mA
1.2V      45.14mA    25.37mA    61.74mA
1.6V      50.34mA    26.49mA    71.04mA
3.1V      52.26mA    27.25mA    74.74mA
4.1V      55.69mA    32.98mA    75.78mA
4.7V      65.7mA     32.98mA    86.67mA
5.1V      65.7mA     32.98mA    96.88mA
6.3V      65.85mA    36.49mA    96.88mA
6.6V      70.9mA     39.7mA     98.46mA
[Pullup]
|Voltage   I(typ)   I(min)   I(max)
-3.3V     74.72mA    67.4mA     93.64mA
-2.3V     74.72mA    66.56mA    93.64mA
-1.5V     71.36mA    49mA       91.07mA
500mV     -22.06mA   -14mA      -30.03mA
1.6V      -50.64mA   -28.8mA    -70.96mA
3.5V      -59.53mA   -32.65mA   -85.92mA
4.2V      -61.43mA   -47.48mA   -87.46mA
4.5V      -69.07mA   -55.13mA   -88.38mA
4.8V      -78.22mA   -63.5mA    -96.83mA
5.4V      -98.3mA    -63.5mA    -119.6mA
5.7V      -98.3mA    -63.5mA    -132mA
6.6V      -98.3mA    -63.5mA    -132mA
[GND_clamp]
|Voltage   I(typ)   I(min)   I(max)
-3.3V     -2.315A    -2.395A    -2.287A
-1.2V     -265.5mA   -356.1mA   -227.2mA
-1.13V    -202.7mA   -292.9mA   -164.2mA
-1.06V    -142.2mA   -231.2mA   -104.1mA
-990mV    -86mA      -171.6mA   -50.76mA
-920mV    -38.84mA   -115.5mA   -15.35mA
-850mV    -11.15mA   -65.63mA   -6.09mA
-780mV    -3.853mA   -27.45mA   -3.961mA
-710mV    -2.153mA   -7.739mA   -2.46mA
-640mV    -1.209mA   -2.169mA   -1.292mA
-570mV    -580.3uA   -846.3uA   -542.8uA
3.28V     342.5uA    239.2uA    398.5uA
[POWER_clamp]
|Voltage   I(typ)   I(min)   I(max)
-3.28V    0A         148.5nA    0A
-3.2V     0A         138.6nA    0A
-3.12V    0A         129.7nA    0A
-3.04V    0A         122nA      0A
-2.96V    0A         115.3nA    0A
-2.8V     0A         105.1nA    0A
-2.6V     0A         96.44nA    0A
-2.4V     0A         90.52nA    0A
-2.16V    0A         84.97nA    0A
-440mV    0A         50.04nA    0A
-400mV    0A         0A         0A
0V        0A         0A         0A
[Ramp]
| variable   typ   min   max
dV/dt_r  1.25832/1.11811n   0.80328/0.93930n   1.55742/0.99875n
dV/dt_f  1.27566/0.99597n   0.77142/0.75892n   1.56814/0.97751n
R_load = 50.000000
[Rising Waveform]
R_fixture= 50.000000
V_fixture= 3.300000
V_fixture_min= 2.700000
V_fixture_max= 3.600000
|time   V(typ)   V(min)   V(max)
0s        1.121V     1.387V     952.6mV
320.3ps   1.124V     1.387V     1.076V
390.4ps   1.125V     1.387V     1.41V
560.6ps   1.15V      1.387V     3.073V
690.7ps   1.341V     1.386V     3.458V
780.8ps   1.782V     1.386V     3.539V
951ps     2.943V     1.389V     3.576V
1.181ns   3.253V     1.432V     3.583V
1.962ns   3.288V     2.686V     3.589V
4.985ns   3.295V     2.695V     3.594V
[Rising Waveform]
R_fixture= 50.000000
V_fixture= 0.0
V_fixture_min= 0.0
V_fixture_max= 0.0
|time   V(typ)   V(min)   V(max)
0s        345.9uV    197.2uV    652.6uV
470.5ps   -2.817mV   136.4uV    -57.24uV
650.7ps   -14.05mV   197.4uV    155.2mV
951ps     37.18mV    -1.039mV   615mV
1.662ns   845.7mV    26.8mV     1.782V
2.192ns   1.473V     512.4mV    2.34V
2.503ns   1.734V     799.3mV    2.456V
3.043ns   1.98V      1.181V     2.541V
3.854ns   2.089V     1.328V     2.585V
4.985ns   2.123V     1.354V     2.606V
[Falling Waveform]
R_fixture= 50.000000
V_fixture= 3.300000
V_fixture_min= 2.700000
V_fixture_max= 3.600000
|time   V(typ)   V(min)   V(max)
0s        3.295V     2.695V     3.594V
600.6ps   3.307V     2.695V     3.554V
750.8ps   3.31V      2.695V     3.357V
991ps     3.277V     2.696V     2.881V
1.201ns   3.09V      2.7V       2.478V
1.772ns   2.264V     2.645V     1.607V
2.342ns   1.586V     2.027V     1.141V
2.693ns   1.359V     1.692V     1.062V
3.123ns   1.25V      1.487V     1.015V
4.985ns   1.121V     1.387V     952.6mV
[Falling Waveform]
R_fixture= 50.000000
V_fixture= 0.0
V_fixture_min= 0.0
V_fixture_max= 0.0
|time   V(typ)   V(min)   V(max)
0s        2.123V     1.354V     2.606V
310.3ps   2.124V     1.354V     2.447V
450.5ps   2.113V     1.354V     1.954V
720.7ps   1.838V     1.355V     619.9mV
870.9ps   1.379V     1.355V     200.2mV
1.011ns   908.1mV    1.348V     37.39mV
1.391ns   71.32mV    1.164V     2.889mV
1.872ns   3.187mV    432.7mV    1.882mV
2.282ns   1.72mV     39.02mV    1.564mV
4.985ns   345.9uV    197.2uV    652.6uV
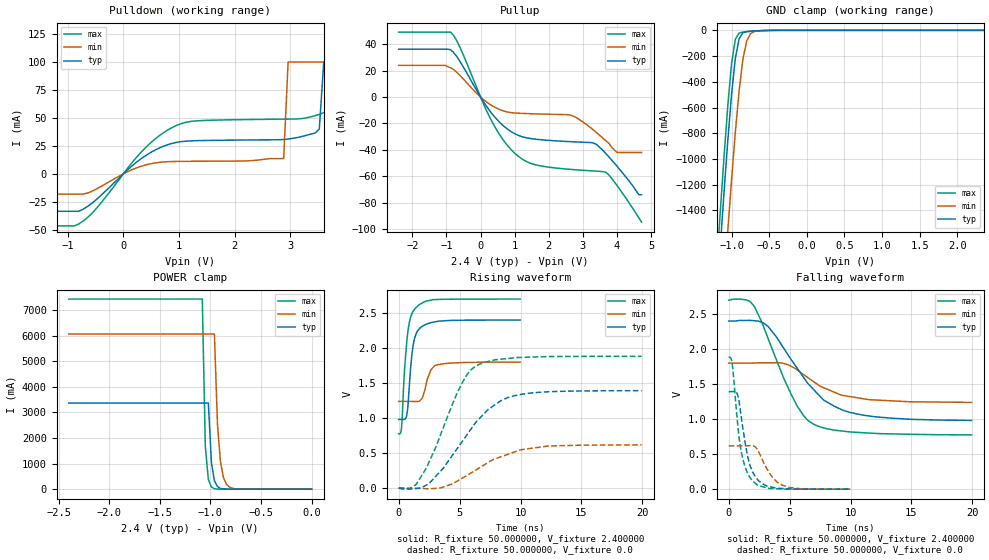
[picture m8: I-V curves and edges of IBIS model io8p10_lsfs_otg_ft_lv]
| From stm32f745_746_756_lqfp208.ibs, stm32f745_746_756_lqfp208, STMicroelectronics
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|   Model io8p10_lsfs_otg_ft_lv
[Model]  io8p10_lsfs_otg_ft_lv
Model_type I/O
Polarity   Non-Inverting
Enable   Active-Low
Vinl =   0.720000V
Vinh =   1.680000V
Vmeas =  1.200000V
Cref =   40.000000pF
Rref =   100.000000M
Vref =   0.0V
C_comp   7.971100pF   7.737700pF   8.264100pF
[Temperature Range]   25.000000   0.125000k   -40.000000
[Pullup Reference]   2.400000V   1.800000V   2.700000V
[Pulldown Reference]   0.0V   0.0V   0.0V
[POWER Clamp Reference]   2.400000V   1.800000V   2.700000V
[GND Clamp Reference]   0.0V   0.0V   0.0V
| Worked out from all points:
|   slope of the pulldown table from 0 to 0.36 V, typ, clamps not added: 24.1 ohm
|   slope of the pullup table from 0 to 0.36 V, typ, clamps not added: 26.8 ohm
|   GND clamp passes 1 mA (typ) near -0.52 V on its own axis
|   POWER clamp passes 1 mA (typ) near -0.81 V on its own axis
|   rising waveform, R_fixture 50.000000, V_fixture 2.400000: 20-80 % time 481ps typ, 595ps min, 491ps max; typ from 0.981 V to 2.4 V
|   rising waveform, R_fixture 50.000000, V_fixture 0.0: 20-80 % time 3.67ns typ, 4.11ns min, 2.72ns max; typ from 0 V to 1.39 V
|   falling waveform, R_fixture 50.000000, V_fixture 2.400000: 20-80 % time 3.73ns typ, 3.39ns min, 2.85ns max; typ from 2.4 V to 0.981 V
|   falling waveform, R_fixture 50.000000, V_fixture 0.0: 20-80 % time 916ps typ, 1.27ns min, 799ps max; typ from 1.39 V to 0 V
[Pulldown]
|Voltage   I(typ)   I(min)   I(max)
-2.4V     -33.44mA   -18.12mA   -46.52mA
-800mV    -33.44mA   -18.12mA   -44.78mA
1.04V     28.81mA    11.14mA    44.91mA
2.88V     30.71mA    13.65mA    48.89mA
2.96V     31.11mA    100mA      48.94mA
3.52V     40mA       100mA      53.15mA
3.6V      100mA      100mA      54.66mA
3.92V     100mA      100mA      60mA
4V        100mA      100mA      100mA
4.4V      100mA      100mA      100mA
4.48V     100mA      100mA      1A
4.8V      100mA      100mA      1A
[Pullup]
|Voltage   I(typ)   I(min)   I(max)
-2.4V     36.21mA    24mA       49.16mA
-880mV    35.81mA    22.16mA    49.16mA
-640mV    28.47mA    17.31mA    39.62mA
320mV     -12.14mA   -6.322mA   -17.91mA
960mV     -27.18mA   -12mA      -41.54mA
1.52V     -31.65mA   -12.71mA   -50.68mA
2.64V     -33.82mA   -13.73mA   -54.81mA
3.36V     -35.34mA   -26.1mA    -56.1mA
3.68V     -43.1mA    -33.3mA    -57.12mA
4V        -52.4mA    -42mA      -67mA
4.64V     -74mA      -42mA      -91.5mA
4.72V     -74mA      -42mA      -94.8mA
[GND_clamp]
|Voltage   I(typ)   I(min)   I(max)
-2.4V     -9.766A    -9.942A    -9.572A
-1.2V     -2.124A    -2.851A    -1.855A
-1.15V    -1.682A    -2.408A    -1.408A
-1.1V     -1.256A    -1.975A    -979.8mA
-1.05V    -854.9mA   -1.556A    -584.5mA
-1V       -496.5mA   -1.158A    -257.5mA
-950mV    -217.7mA   -789.6mA   -69.52mA
-900mV    -65.57mA   -469.8mA   -21.5mA
-850mV    -19.64mA   -226.4mA   -13.56mA
-800mV    -9.753mA   -84.21mA   -10.47mA
-700mV    -4.923mA   -9.884mA   -5.807mA
2.35V     0A         0A         0A
[POWER_clamp]
|Voltage   I(typ)   I(min)   I(max)
-2.4V     3.365A     6.064A     7.43A
-1.08V    3.365A     6.064A     7.43A
-1.05V    3.365A     6.064A     1.669A
-1.02V    3.365A     6.064A     375mA
-990mV    1.047A     6.064A     84.24mA
-960mV    325.6mA    6.064A     18.93mA
-930mV    101.3mA    2.529A     4.252mA
-900mV    31.51mA    1.055A     955.2uA
-870mV    9.804mA    440.1mA    214.6uA
-840mV    3.05mA     183.6mA    74uA
-720mV    28.58uA    5.557mA    74uA
0V        0A         0A         0A
[Ramp]
| variable   typ   min   max
dV/dt_r  0.83526/3.66699n   0.37067/4.10682n   1.12860/2.71703n
dV/dt_f  0.84794/3.73359n   0.33612/3.41033n   1.15433/2.85226n
R_load = 50.000000
[Rising Waveform]
R_fixture= 50.000000
V_fixture= 2.400000
V_fixture_min= 1.800000
V_fixture_max= 2.700000
|time   V(typ)   V(min)   V(max)
0s        981.5mV    1.239V     775.1mV
220.2ps   981.2mV    1.239V     836.9mV
440.4ps   982.5mV    1.239V     1.575V
640.6ps   1.022V     1.239V     2.039V
820.8ps   1.323V     1.239V     2.315V
1.101ns   1.936V     1.238V     2.497V
1.421ns   2.199V     1.237V     2.578V
1.922ns   2.31V      1.282V     2.642V
2.963ns   2.374V     1.75V      2.692V
9.97ns    2.4V       1.8V       2.7V
[Rising Waveform]
R_fixture= 50.000000
V_fixture= 0.0
V_fixture_min= 0.0
V_fixture_max= 0.0
|time   V(typ)   V(min)   V(max)
0s        15.03uV    7.25uV     -90.52uV
1.441ns   -5.118mV   71.59uV    56.85mV
2.482ns   63.79mV    -7.427mV   369.4mV
3.483ns   252.9mV    6.388mV    784.8mV
5.165ns   654.5mV    138.2mV    1.488V
5.766ns   802.3mV    199.3mV    1.656V
6.527ns   977mV      280mV      1.761V
8.368ns   1.247V     447.2mV    1.841V
10.21ns   1.344V     553.4mV    1.868V
19.94ns   1.392V     617.9mV    1.882V
[Falling Waveform]
R_fixture= 50.000000
V_fixture= 2.400000
V_fixture_min= 1.800000
V_fixture_max= 2.700000
|time   V(typ)   V(min)   V(max)
0s        2.4V       1.8V       2.7V
1.441ns   2.41V      1.8V       2.702V
2.122ns   2.405V     1.801V     2.604V
3.243ns   2.321V     1.804V     2.148V
5.125ns   1.851V     1.754V     1.357V
6.126ns   1.601V     1.638V     1.055V
6.927ns   1.431V     1.54V      932.6mV
7.808ns   1.27V      1.447V     874.1mV
10.41ns   1.078V     1.309V     812.2mV
19.94ns   981.5mV    1.239V     775.1mV
[Falling Waveform]
R_fixture= 50.000000
V_fixture= 0.0
V_fixture_min= 0.0
V_fixture_max= 0.0
|time   V(typ)   V(min)   V(max)
0s        1.392V     617.9mV    1.882V
300.3ps   1.393V     617.9mV    1.779V
760.8ps   1.329V     617.8mV    889.3mV
1.041ns   1.024V     617.6mV    528.4mV
1.562ns   464.3mV    619.2mV    225.2mV
1.922ns   263.9mV    621mV      123.9mV
2.683ns   86.98mV    450.9mV    40.57mV
3.624ns   25.3mV     161mV      7.392mV
4.404ns   9.474mV    56.33mV    2.434mV
9.97ns    15.03uV    7.25uV     -90.52uV
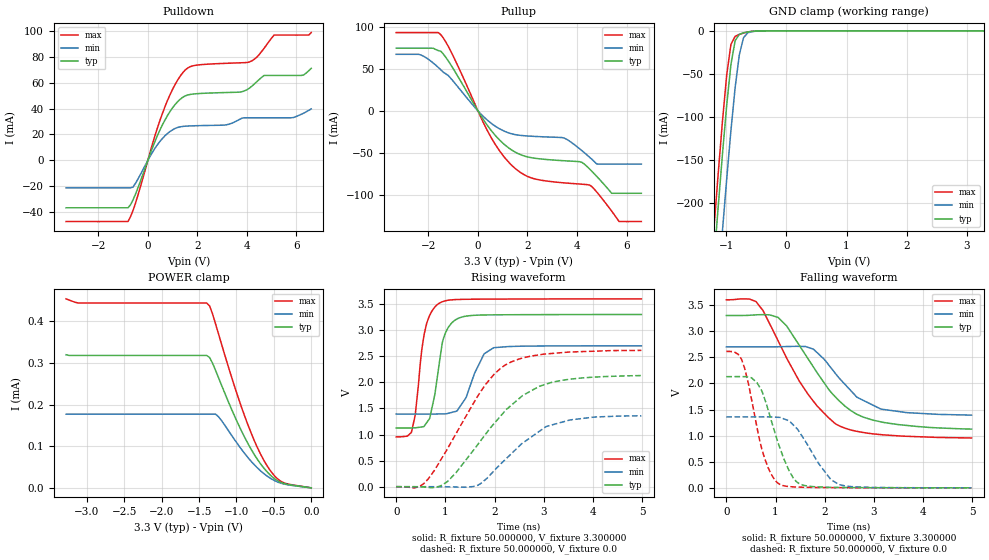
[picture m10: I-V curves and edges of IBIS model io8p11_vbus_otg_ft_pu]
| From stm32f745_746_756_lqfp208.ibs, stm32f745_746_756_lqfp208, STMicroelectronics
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|   Model io8p11_vbus_otg_ft_pu
[Model]  io8p11_vbus_otg_ft_pu
Model_type I/O
Polarity   Non-Inverting
Enable   Active-Low
Vinl =   0.990000V
Vinh =   2.310000V
Vmeas =  1.650000V
Cref =   30.000000pF
Rref =   100.000000M
Vref =   0.0V
C_comp   3.304800pF   3.199300pF   3.429300pF
[Temperature Range]   25.000000   0.125000k   -40.000000
[Pullup Reference]   3.300000V   2.700000V   3.600000V
[Pulldown Reference]   0.0V   0.0V   0.0V
[POWER Clamp Reference]   3.300000V   2.700000V   3.600000V
[GND Clamp Reference]   0.0V   0.0V   0.0V
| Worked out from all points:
|   slope of the pulldown table from 0 to 0.495 V, typ, clamps not added: 20.9 ohm
|   slope of the pullup table from 0 to 0.495 V, typ, clamps not added: 22.6 ohm
|   GND clamp passes 1 mA (typ) near -0.61 V on its own axis
|   rising waveform, R_fixture 50.000000, V_fixture 3.300000: 20-80 % time 232ps typ, 349ps min, 205ps max; typ from 1.12 V to 3.3 V
|   rising waveform, R_fixture 50.000000, V_fixture 0.0: 20-80 % time 1.17ns typ, 993ps min, 1.02ns max; typ from 0.001 V to 2.13 V
|   falling waveform, R_fixture 50.000000, V_fixture 3.300000: 20-80 % time 1.03ns typ, 820ps min, 1.01ns max; typ from 3.3 V to 1.12 V
|   falling waveform, R_fixture 50.000000, V_fixture 0.0: 20-80 % time 451ps typ, 560ps min, 372ps max; typ from 2.13 V to 0.001 V
[Pulldown]
|Voltage   I(typ)   I(min)   I(max)
-3.3V     -36.41mA   -21.08mA   -47.04mA
-800mV    -36.41mA   -21.08mA   -47.04mA
-600mV    -30.48mA   -20.53mA   -38.65mA
700mV     31.4mA     19.11mA    41.71mA
1.2V      45.15mA    25.37mA    61.75mA
1.6V      50.35mA    26.5mA     71.06mA
3.1V      52.28mA    27.26mA    74.76mA
4.1V      55.64mA    32.87mA    75.8mA
4.7V      65.47mA    32.87mA    86.49mA
5.1V      65.47mA    32.87mA    96.56mA
6.2V      65.47mA    35.57mA    96.56mA
6.6V      70.92mA    39.71mA    98.46mA
[Pullup]
|Voltage   I(typ)   I(min)   I(max)
-3.3V     74.7mA     67.42mA    93.32mA
-2.3V     74.7mA     66.58mA    93.32mA
-1.5V     71.16mA    49mA       90.81mA
-1V       50.42mA    35.44mA    65.38mA
500mV     -22.06mA   -14mA      -30.03mA
1.6V      -50.64mA   -28.81mA   -70.96mA
3.5V      -59.52mA   -32.65mA   -85.91mA
4.5V      -69.06mA   -55.12mA   -88.39mA
4.8V      -78.22mA   -63.4mA    -96.84mA
5.4V      -98.3mA    -63.4mA    -119.6mA
5.7V      -98.3mA    -63.4mA    -132mA
6.6V      -98.3mA    -63.4mA    -132mA
[GND_clamp]
|Voltage   I(typ)   I(min)   I(max)
-3.3V     -2.319A    -2.398A    -2.292A
-1.2V     -265.6mA   -356.2mA   -227.3mA
-1.13V    -202.8mA   -293mA     -164.3mA
-1.06V    -142.3mA   -231.2mA   -104.3mA
-990mV    -86.15mA   -171.7mA   -51mA
-920mV    -39.05mA   -115.6mA   -15.71mA
-850mV    -11.4mA    -65.74mA   -6.366mA
-780mV    -4.046mA   -27.6mA    -4.153mA
-710mV    -2.285mA   -7.882mA   -2.591mA
-640mV    -1.291mA   -2.274mA   -1.367mA
-570mV    -618uA     -909.9uA   -567.3uA
3.28V     0A         0A         0A
[POWER_clamp]
|Voltage   I(typ)   I(min)   I(max)
-3.28V    319.9uA    177.1uA    454.3uA
-3.12V    318.3uA    177.1uA    444.3uA
-1.4V     318.3uA    177.1uA    444.3uA
-1.36V    313.4uA    177.1uA    437.2uA
-1.28V    282.3uA    177.1uA    394.1uA
-1.24V    264.6uA    170.9uA    369.7uA
-920mV    131.9uA    89.38uA    187.2uA
-760mV    79.47uA    55.16uA    112.7uA
-640mV    48.78uA    35.06uA    68.06uA
-520mV    26.21uA    20.13uA    35uA
-400mV    12.52uA    10.84uA    14.88uA
0V        0A         0A         0A
[Ramp]
| variable   typ   min   max
dV/dt_r  1.25935/1.15725n   0.80097/0.98107n   1.56004/1.01857n
dV/dt_f  1.27440/1.00919n   0.76632/0.79241n   1.56869/1.00691n
R_load = 50.000000
[Rising Waveform]
R_fixture= 50.000000
V_fixture= 3.300000
V_fixture_min= 2.700000
V_fixture_max= 3.600000
|time   V(typ)   V(min)   V(max)
0s        1.125V     1.393V     955.6mV
310.3ps   1.127V     1.393V     1.045V
390.4ps   1.129V     1.393V     1.407V
570.6ps   1.162V     1.393V     2.93V
680.7ps   1.308V     1.393V     3.283V
880.9ps   2.398V     1.395V     3.518V
961ps     2.84V      1.396V     3.552V
1.131ns   3.141V     1.425V     3.581V
1.982ns   3.293V     2.663V     3.595V
4.985ns   3.3V       2.7V       3.599V
[Rising Waveform]
R_fixture= 50.000000
V_fixture= 0.0
V_fixture_min= 0.0
V_fixture_max= 0.0
|time   V(typ)   V(min)   V(max)
0s        1.433mV    1.237mV    1.778mV
560.6ps   -5.92mV    1.226mV    59.24mV
951ps     39.99mV    17.18uV    584.8mV
1.662ns   813.1mV    29.6mV     1.742V
1.982ns   1.201V     298mV      2.145V
2.232ns   1.473V     534.3mV    2.341V
2.573ns   1.749V     837.9mV    2.467V
3.053ns   1.967V     1.155V     2.544V
4.034ns   2.1V       1.336V     2.597V
4.985ns   2.129V     1.359V     2.612V
[Falling Waveform]
R_fixture= 50.000000
V_fixture= 3.300000
V_fixture_min= 2.700000
V_fixture_max= 3.600000
|time   V(typ)   V(min)   V(max)
0s        3.3V       2.7V       3.599V
600.6ps   3.312V     2.7V       3.567V
750.8ps   3.315V     2.7V       3.386V
1.051ns   3.264V     2.701V     2.819V
1.481ns   2.732V     2.709V     2.048V
1.772ns   2.312V     2.655V     1.658V
2.252ns   1.707V     2.149V     1.209V
2.653ns   1.409V     1.739V     1.083V
3.143ns   1.264V     1.509V     1.02V
4.985ns   1.125V     1.393V     955.6mV
[Falling Waveform]
R_fixture= 50.000000
V_fixture= 0.0
V_fixture_min= 0.0
V_fixture_max= 0.0
|time   V(typ)   V(min)   V(max)
0s        2.129V     1.359V     2.612V
310.3ps   2.13V      1.359V     2.458V
460.5ps   2.117V     1.359V     1.946V
620.6ps   2.015V     1.359V     1.171V
840.8ps   1.523V     1.361V     407.4mV
1.081ns   786.8mV    1.35V      71.87mV
1.471ns   88mV       1.092V     15.3mV
1.872ns   18.78mV    473.8mV    7.93mV
2.292ns   9.007mV    62.59mV    5.047mV
4.985ns   1.433mV    1.237mV    1.778mV
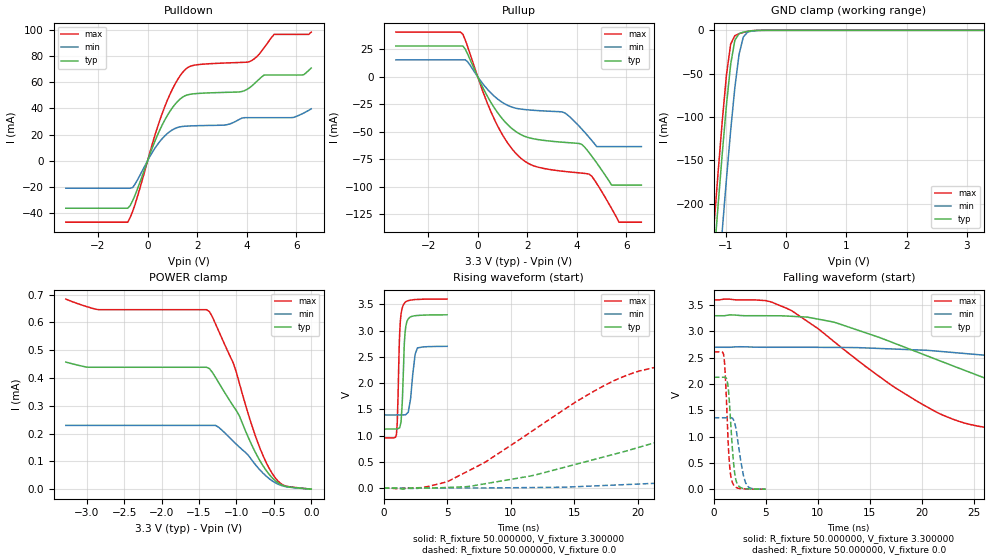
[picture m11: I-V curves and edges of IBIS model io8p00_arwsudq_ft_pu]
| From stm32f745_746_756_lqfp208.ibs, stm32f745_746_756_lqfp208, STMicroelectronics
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|   Model io8p00_arwsudq_ft_pu
[Model]  io8p00_arwsudq_ft_pu
Model_type I/O
Polarity   Non-Inverting
Enable   Active-Low
Vinl =   0.990000V
Vinh =   2.310000V
Vmeas =  1.650000V
Cref =   50.000000pF
Rref =   100.000000M
Vref =   0.0V
C_comp   2.905500pF   2.831700pF   2.987900pF
[Temperature Range]   25.000000   0.125000k   -40.000000
[Pullup Reference]   3.300000V   2.700000V   3.600000V
[Pulldown Reference]   0.0V   0.0V   0.0V
[POWER Clamp Reference]   3.300000V   2.700000V   3.600000V
[GND Clamp Reference]   0.0V   0.0V   0.0V
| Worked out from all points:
|   slope of the pulldown table from 0 to 0.495 V, typ, clamps not added: 20.9 ohm
|   slope of the pullup table from 0 to 0.495 V, typ, clamps not added: 22.6 ohm
|   GND clamp passes 1 mA (typ) near -0.62 V on its own axis
|   rising waveform, R_fixture 50.000000, V_fixture 3.300000: 20-80 % time 210ps typ, 337ps min, 188ps max; typ from 1.12 V to 3.3 V
|   rising waveform, R_fixture 50.000000, V_fixture 0.0: 20-80 % time 19.7ns typ, 50.8ns min, 10.3ns max; typ from 0.001 V to 2.13 V
|   falling waveform, R_fixture 50.000000, V_fixture 3.300000: 20-80 % time 18.5ns typ, 38.4ns min, 11.4ns max; typ from 3.3 V to 1.12 V
|   falling waveform, R_fixture 50.000000, V_fixture 0.0: 20-80 % time 460ps typ, 653ps min, 369ps max; typ from 2.13 V to 0.001 V
[Pulldown]
|Voltage   I(typ)   I(min)   I(max)
-3.3V     -36.39mA   -21.07mA   -47.09mA
-800mV    -36.39mA   -21.07mA   -47.09mA
-600mV    -30.5mA    -20.54mA   -38.69mA
700mV     31.4mA     19.11mA    41.71mA
1.2V      45.15mA    25.37mA    61.75mA
1.6V      50.35mA    26.5mA     71.06mA
3.1V      52.28mA    27.26mA    74.75mA
4.1V      55.65mA    32.92mA    75.79mA
4.7V      65.56mA    32.92mA    86.49mA
5.1V      65.56mA    32.92mA    96.69mA
6.3V      65.85mA    36.49mA    96.69mA
6.6V      70.9mA     39.7mA     98.44mA
[Pullup]
|Voltage   I(typ)   I(min)   I(max)
-3.3V     28mA       15.42mA    40.61mA
-700mV    28mA       15.42mA    40.61mA
-400mV    20.3mA     13.47mA    26.92mA
600mV     -25.77mA   -16.23mA   -35.13mA
1.6V      -50.64mA   -28.8mA    -70.96mA
3.5V      -59.52mA   -32.65mA   -85.91mA
4.2V      -61.44mA   -47.49mA   -87.45mA
4.5V      -69.08mA   -55.12mA   -88.39mA
4.8V      -78.23mA   -63.4mA    -96.87mA
5.4V      -98.3mA    -63.4mA    -119.6mA
5.7V      -98.3mA    -63.4mA    -132mA
6.6V      -98.3mA    -63.4mA    -132mA
[GND_clamp]
|Voltage   I(typ)   I(min)   I(max)
-3.3V     -2.32A     -2.398A    -2.294A
-1.2V     -266mA     -356.2mA   -228.4mA
-1.13V    -203.2mA   -293mA     -165.3mA
-1.06V    -142.7mA   -231.3mA   -105.2mA
-990mV    -86.51mA   -171.7mA   -51.78mA
-920mV    -39.3mA    -115.7mA   -15.93mA
-850mV    -11.37mA   -65.76mA   -6.097mA
-780mV    -3.83mA    -27.55mA   -3.88mA
-710mV    -2.09mA    -7.747mA   -2.382mA
-640mV    -1.147mA   -2.129mA   -1.22mA
-570mV    -523.9uA   -800uA     -476.9uA
3.28V     0A         0A         0A
[POWER_clamp]
|Voltage   I(typ)   I(min)   I(max)
-3.28V    457.2uA    229.4uA    683.8uA
-2.84V    438.5uA    229.4uA    645.6uA
-1.36V    433.5uA    229.4uA    638.5uA
-1.24V    384.6uA    223.2uA    570.8uA
-1.04V    298.3uA    171.8uA    452.6uA
-960mV    263.4uA    151.4uA    380.6uA
-760mV    139.5uA    92.81uA    202.3uA
-640mV    82.23uA    56.4uA     118uA
-560mV    52.51uA    37.37uA    73.96uA
-440mV    21.63uA    17.4uA     27.8uA
-360mV    11.48uA    10.27uA    13.1uA
0V        0A         0A         0A
[Ramp]
| variable   typ   min   max
dV/dt_r  1.27717/19.72448n   0.81591/50.92219n   1.56687/10.33428n
dV/dt_f  1.30620/18.45855n   0.78408/38.50253n   1.58713/11.33427n
R_load = 50.000000
[Rising Waveform]
R_fixture= 50.000000
V_fixture= 3.300000
V_fixture_min= 2.700000
V_fixture_max= 3.600000
|time   V(typ)   V(min)   V(max)
0s        1.125V     1.393V     954.7mV
1.001ns   1.127V     1.393V     1.013V
1.071ns   1.129V     1.393V     1.262V
1.271ns   1.16V      1.393V     3.011V
1.371ns   1.271V     1.393V     3.316V
1.532ns   2.089V     1.393V     3.479V
1.672ns   2.923V     1.395V     3.533V
1.932ns   3.222V     1.446V     3.569V
2.653ns   3.287V     2.668V     3.592V
4.985ns   3.3V       2.7V       3.6V
[Rising Waveform]
R_fixture= 50.000000
V_fixture= 0.0
V_fixture_min= 0.0
V_fixture_max= 0.0
|time   V(typ)   V(min)   V(max)
0s        1.09mV     1.043mV    1.153mV
5.005ns   12.66mV    2.763mV    122.5mV
11.51ns   229.2mV    10.71mV    1.06V
19.02ns   703.3mV    67.36mV    2.14V
27.53ns   1.298V     167.5mV    2.488V
38.54ns   1.854V     361.5mV    2.577V
57.56ns   2.068V     712mV      2.609V
88.09ns   2.119V     1.133V     2.613V
115.1ns   2.128V     1.293V     2.613V
249.2ns   2.13V      1.36V      2.613V
[Falling Waveform]
R_fixture= 50.000000
V_fixture= 3.300000
V_fixture_min= 2.700000
V_fixture_max= 3.600000
|time   V(typ)   V(min)   V(max)
0s        3.3V       2.7V       3.6V
5.506ns   3.299V     2.7V       3.563V
11.51ns   3.18V      2.697V     2.815V
22.02ns   2.42V      2.617V     1.409V
31.53ns   1.728V     2.436V     1.076V
38.54ns   1.42V      2.267V     1.025V
47.05ns   1.272V     2.057V     998.1mV
63.56ns   1.185V     1.728V     970.4mV
86.59ns   1.148V     1.528V     957.8mV
249.2ns   1.125V     1.393V     954.7mV
[Falling Waveform]
R_fixture= 50.000000
V_fixture= 0.0
V_fixture_min= 0.0
V_fixture_max= 0.0
|time   V(typ)   V(min)   V(max)
0s        2.13V      1.36V      2.613V
981ps     2.131V     1.36V      2.514V
1.151ns   2.121V     1.359V     1.99V
1.311ns   2.035V     1.359V     1.24V
1.491ns   1.678V     1.361V     528.7mV
1.792ns   766.8mV    1.353V     128.2mV
2.182ns   138mV      1.095V     31.6mV
2.843ns   15.18mV    270mV      6.269mV
3.143ns   7.586mV    88.96mV    4.725mV
4.985ns   1.09mV     1.043mV    1.153mV
